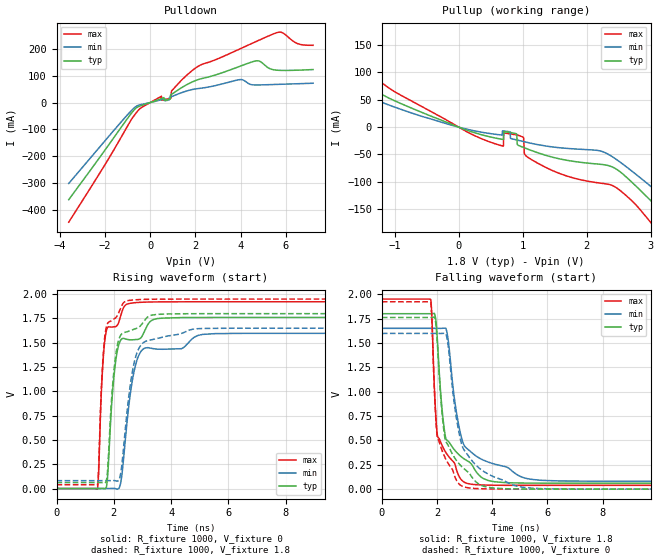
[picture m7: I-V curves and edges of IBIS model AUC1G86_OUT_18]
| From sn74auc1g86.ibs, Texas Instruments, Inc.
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[Model]   AUC1G86_OUT_18
Model_type  Output
Vref =   0
Rref =   1000
Cref =   30p
Vmeas =   0.9
| variable   typ   min   max
C_comp   7.36pF   0.68pF   22.01pF
| C_pullup   7.69pF   0.68pF   22.01pF
| C_pulldown   7.03pF   0.72pF   15.91pF
[Temperature Range]   40   100   -40
| Ambient temperature   25   85   -40
[Voltage range]   1.8   1.65   1.95
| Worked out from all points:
|   slope of the pulldown table from 0 to 0.27 V, typ, clamps not added: 34.4 ohm
|   slope of the pullup table from 0 to 0.27 V, typ, clamps not added: 24.5 ohm
|   rising waveform, R_fixture 1000, V_fixture 0: 20-80 % time 289ps typ, 421ps min, 196ps max; typ from 0 V to 1.76 V
|   falling waveform, R_fixture 1000, V_fixture 1.8: 20-80 % time 586ps typ, 698ps min, 392ps max; typ from 1.8 V to 0.061 V
|   rising waveform, R_fixture 1000, V_fixture 1.8: 20-80 % time 285ps typ, 413ps min, 193ps max; typ from 0.061 V to 1.8 V
|   falling waveform, R_fixture 1000, V_fixture 0: 20-80 % time 544ps typ, 716ps min, 360ps max; typ from 1.76 V to 0 V
[Pulldown]
| AUC1G86_OUT_18
|   Voltage   I(typ)   I(min)   I(max)
-3.6V     -362.3mA   -301.8mA   -446.4mA
-665mV    -23.41mA   -16.88mA   -43.39mA
495mV     15.02mA    10.74mA    23.53mA
885mV     12.99mA    20.07mA    16.03mA
925mV     29.61mA    21.43mA    17.26mA
955mV     31.22mA    22.47mA    44.6mA
1.985V    81.61mA    50.75mA    127.7mA
3.975V    135.8mA    85.83mA    200.7mA
4.69V     155.8mA    65.71mA    228.3mA
5.665V    120.6mA    68.06mA    262.5mA
6.52V     121mA      70.38mA    219.9mA
7.2V      123.3mA    72.23mA    213.8mA
[Pullup]
| AUC1G86_OUT_18
|   Voltage   I(typ)   I(min)   I(max)
-3.6V     267.7mA    221.6mA    318.8mA
-2.795V   191.4mA    153.2mA    238.4mA
-2.29V    145.5mA    113.6mA    187.8mA
130mV     -5.635mA   -3.795mA   -8.57mA
695mV     -22.64mA   -6.943mA   -34.84mA
965mV     -34.98mA   -25.01mA   -16.26mA
1.155V    -43.49mA   -30.08mA   -60.54mA
2.25V     -68.45mA   -44.86mA   -103mA
3.11V     -147mA     -118.7mA   -189.7mA
3.46V     -188.2mA   -153mA     -239.2mA
3.93V     -243.8mA   -199.8mA   -304.9mA
7.2V      -626.9mA   -529.9mA   -752.7mA
[Ramp]
| AUC1G86_OUT_18
| variable   typ   min   max
dV/dt_r   1.06/2.90E-10   0.96/4.22E-10   1.16/1.97E-10
dV/dt_f   1.05/5.86E-10   0.94/6.98E-10   1.15/3.94E-10
R_load = 1000
[Rising Waveform]
| AUC1G86_OUT_18
R_fixture =   1000
C_fixture =   0
L_fixture =   0
V_fixture =   0
V_fixture_min = 0
V_fixture_max = 0
|   Time   V(typ)   V(min)   V(max)
0s        7.914nV    27.05nV    1.126nV
1.425ns   3.707uV    -3.606uV   -5.358mV
1.585ns   503.8uV    -5.307uV   1.118V
1.715ns   3.739mV    6.158uV    1.588V
2.085ns   1.353V     -4.157mV   1.67V
2.26ns    1.535V     96.24mV    1.798V
2.49ns    1.533V     766.2mV    1.901V
2.985ns   1.567V     1.425V     1.917V
5.095ns   1.761V     1.586V     1.922V
21.57ns   1.761V     1.597V     1.922V
[Falling Waveform]
| AUC1G86_OUT_18
R_fixture =   1000
C_fixture =   0
L_fixture =   0
V_fixture =   1.8
V_fixture_min = 1.65
V_fixture_max = 1.95
|   Time   V(typ)   V(min)   V(max)
0s        1.8V       1.65V      1.95V
1.77ns    1.8V       1.65V      1.946V
1.925ns   1.786V     1.65V      914mV
2.015ns   1.52V      1.65V      548.8mV
2.155ns   905mV      1.649V     467.3mV
2.315ns   524.7mV    1.651V     378.5mV
2.73ns    371.5mV    744mV      178.2mV
3.095ns   290.6mV    414.5mV    59.21mV
5.77ns    61.78mV    90.79mV    38.84mV
21.57ns   61.08mV    81.15mV    38.69mV
[Rising Waveform]
| AUC1G86_OUT_18
R_fixture =   1000
C_fixture =   0
L_fixture =   0
V_fixture =   1.8
V_fixture_min = 1.65
V_fixture_max = 1.95
|   Time   V(typ)   V(min)   V(max)
0s        61.05mV    81.14mV    38.68mV
1.425ns   61.05mV    81.14mV    33.52mV
1.585ns   61.53mV    81.14mV    1.156V
1.71ns    63.8mV     81.15mV    1.619V
2.07ns    1.381V     78.87mV    1.759V
2.24ns    1.579V     158.5mV    1.858V
2.455ns   1.613V     772.7mV    1.932V
2.95ns    1.682V     1.478V     1.946V
4.75ns    1.799V     1.639V     1.95V
21.57ns   1.8V       1.65V      1.95V
[Falling Waveform]
| AUC1G86_OUT_18
R_fixture =   1000
C_fixture =   0
L_fixture =   0
V_fixture =   0
V_fixture_min = 0
V_fixture_max = 0
|   Time   V(typ)   V(min)   V(max)
0s        1.761V     1.597V     1.922V
1.77ns    1.761V     1.597V     1.918V
1.925ns   1.746V     1.597V     885.1mV
2.01ns    1.5V       1.597V     530.9mV
2.145ns   897.9mV    1.597V     426.4mV
2.295ns   512.2mV    1.598V     321.1mV
2.705ns   294.2mV    724.8mV    89.8mV
2.985ns   208.1mV    400mV      22.44mV
5.385ns   1.017mV    11.21mV    207.5uV
21.57ns   29.95uV    6.816uV    12.82uV
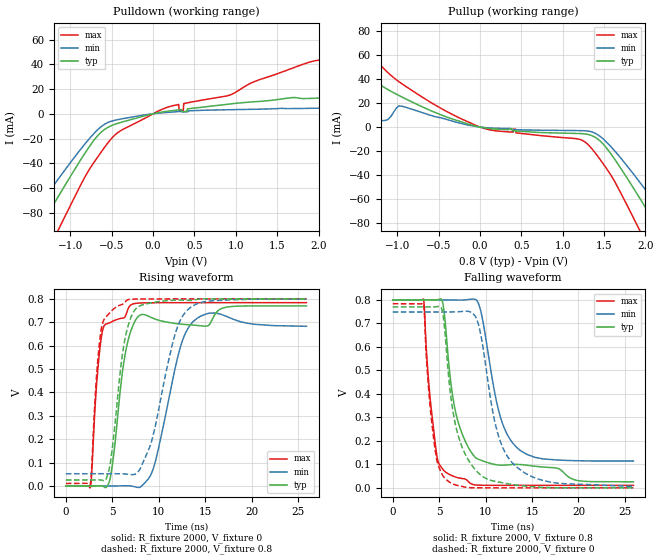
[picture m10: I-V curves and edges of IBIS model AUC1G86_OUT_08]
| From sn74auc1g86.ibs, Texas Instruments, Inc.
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[Model]   AUC1G86_OUT_08
Model_type  Output
Vref =   0
Rref =   2000
Cref =   15p
Vmeas =   0.4
| variable   typ   min   max
C_comp   5.94pF   3.04pF   6.96pF
| C_pullup   5.29pF   3.04pF   6.90pF
| C_pulldown   6.59pF   5.94pF   6.96pF
[Temperature Range]   40   100   -40
| Ambient temperature   25   85   -40
[Voltage range]   0.8   0.8   0.8
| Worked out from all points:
|   slope of the pulldown table from 0 to 0.12 V, typ, clamps not added: 76.6 ohm
|   slope of the pullup table from 0 to 0.12 V, typ, clamps not added: 92.8 ohm
|   rising waveform, R_fixture 2000, V_fixture 0: 20-80 % time 1.45ns typ, 2.18ns min, 877ps max; typ from 0 V to 0.77 V
|   falling waveform, R_fixture 2000, V_fixture 0.8: 20-80 % time 2.25ns typ, 2.13ns min, 1.09ns max; typ from 0.8 V to 0.026 V
|   rising waveform, R_fixture 2000, V_fixture 0.8: 20-80 % time 1.4ns typ, 2.47ns min, 819ps max; typ from 0.025 V to 0.8 V
|   falling waveform, R_fixture 2000, V_fixture 0: 20-80 % time 1.95ns typ, 2.34ns min, 1.05ns max; typ from 0.77 V to 0 V
[Pulldown]
| AUC1G86_OUT_08
|   Voltage   I(typ)   I(min)   I(max)
-3.6V     -346.6mA   -291.5mA   -421.7mA
-1.64V    -122.7mA   -99.17mA   -160.6mA
-1.38V    -93.18mA   -74.45mA   -125.6mA
-1.16V    -68.41mA   -53.98mA   -95.77mA
-635mV    -15.34mA   -10.82mA   -31.6mA
-440mV    -8mA       -4.928mA   -15.86mA
-95mV     -1.581mA   -843.7uA   -3.47mA
225mV     2.447mA    1.368mA    6.296mA
925mV     7.884mA    3.293mA    15.05mA
1.975V    12.59mA    4.484mA    43.08mA
2.36V     13.67mA    4.871mA    39.02mA
7.2V      27.98mA    10.42mA    69.6mA
[Pullup]
| AUC1G86_OUT_08
|   Voltage   I(typ)   I(min)   I(max)
-3.6V     104.9mA    15mA       186mA
-3.045V   84.5mA     15.73mA    162.1mA
-2.14V    43.16mA    20.13mA    129.2mA
-1.585V   27.7mA     11.51mA    82.42mA
-1.305V   38.36mA    6.702mA    59.62mA
-975mV    26.18mA    17.64mA    37.65mA
-245mV    4.854mA    3.296mA    7.479mA
1.35V     -7.075mA   -3.979mA   -17.87mA
1.865V    -51.99mA   -40mA      -77.14mA
2.1V      -78.19mA   -61.38mA   -109.4mA
2.38V     -110mA     -87.7mA    -147.8mA
7.2V      -663.2mA   -564.8mA   -796.4mA
[Ramp]
| AUC1G86_OUT_08
| variable   typ   min   max
dV/dt_r   0.47/1.46E-09   0.45/2.44E-09   0.47/8.79E-10
dV/dt_f   0.47/2.24E-09   0.41/2.14E-09   0.48/1.09E-09
R_load = 2000
[Rising Waveform]
| AUC1G86_OUT_08
R_fixture =   2000
C_fixture =   0
L_fixture =   0
V_fixture =   0
V_fixture_min = 0
V_fixture_max = 0
|   Time   V(typ)   V(min)   V(max)
0s        8.345nV    47.23nV    533.1pV
2.655ns   -5.559uV   -3.931uV   -4.651mV
3.665ns   677.1uV    -5.562uV   587.1mV
4.655ns   14.54mV    -20.56uV   696.8mV
6.17ns    509.2mV    527.7uV    717.6mV
6.995ns   662.7mV    -4.108uV   774.3mV
9.29ns    718.8mV    60.33mV    783.4mV
12.24ns   692.7mV    581mV      783.6mV
13.81ns   687.7mV    706.7mV    783.7mV
25.92ns   769.9mV    682.8mV    783.7mV
[Falling Waveform]
| AUC1G86_OUT_08
R_fixture =   2000
C_fixture =   0
L_fixture =   0
V_fixture =   0.8
V_fixture_min = 0.8
V_fixture_max = 0.8
|   Time   V(typ)   V(min)   V(max)
0s        800mV      800mV      800mV
3.32ns    800mV      800mV      803.7mV
3.88ns    800mV      800mV      445.4mV
4.625ns   799.1mV    800mV      173.2mV
5.695ns   686.6mV    800mV      66.96mV
6.805ns   316.5mV    799.4mV    45.4mV
8.92ns    128.4mV    801.9mV    12.26mV
11.48ns   96.84mV    316.8mV    10.71mV
13.25ns   99.79mV    176.3mV    10.67mV
25.92ns   25.64mV    114.2mV    10.62mV
[Rising Waveform]
| AUC1G86_OUT_08
R_fixture =   2000
C_fixture =   0
L_fixture =   0
V_fixture =   0.8
V_fixture_min = 0.8
V_fixture_max = 0.8
|   Time   V(typ)   V(min)   V(max)
0s        25.46mV    52.15mV    10.6mV
2.63ns    25.46mV    52.16mV    8.517mV
3.265ns   25.59mV    52.17mV    447.5mV
3.74ns    25.47mV    52.15mV    651.2mV
4.655ns   70.32mV    52.21mV    737.5mV
5.255ns   250.9mV    52.26mV    760.4mV
6.365ns   627.8mV    51.1mV     786mV
7.775ns   765.8mV    60.4mV     799.4mV
13.07ns   793.7mV    751.5mV    799.9mV
25.92ns   799.9mV    798.8mV    800mV
[Falling Waveform]
| AUC1G86_OUT_08
R_fixture =   2000
C_fixture =   0
L_fixture =   0
V_fixture =   0
V_fixture_min = 0
V_fixture_max = 0
|   Time   V(typ)   V(min)   V(max)
0s        770mV      748.6mV    783.8mV
3.315ns   770mV      748.6mV    785.6mV
4.52ns    770mV      748.6mV    174mV
5.34ns    753.6mV    748.6mV    55.85mV
5.885ns   533.4mV    748.6mV    30.91mV
7.145ns   209.8mV    749.8mV    8.645mV
9.735ns   47.09mV    593.9mV    150uV
11.23ns   26.13mV    242.7mV    85.51uV
13.16ns   12.35mV    95.06mV    59.07uV
25.92ns   83.55uV    5.897mV    19.69uV
